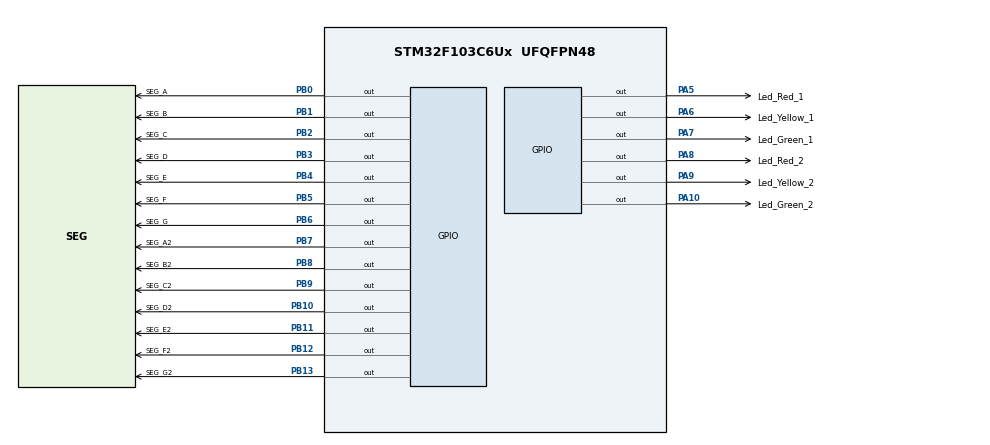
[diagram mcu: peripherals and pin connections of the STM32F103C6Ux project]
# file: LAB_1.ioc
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Mcu.Family=STM32F1
Mcu.Name=STM32F103C6Ux
Mcu.Package=UFQFPN48
NVIC.PriorityGroup=NVIC_PRIORITYGROUP_4
PA10.GPIO_Label=Led_Green_2
PA10.Signal=GPIO_Output
PA5.GPIO_Label=Led_Red_1
PA5.Signal=GPIO_Output
PA6.GPIO_Label=Led_Yellow_1
PA6.Signal=GPIO_Output
PA7.GPIO_Label=Led_Green_1
PA7.Signal=GPIO_Output
PA8.GPIO_Label=Led_Red_2
PA8.Signal=GPIO_Output
PA9.GPIO_Label=Led_Yellow_2
PA9.Signal=GPIO_Output
PB0.GPIO_Label=SEG_A
PB0.Signal=GPIO_Output
PB1.GPIO_Label=SEG_B
PB1.Signal=GPIO_Output
PB10.GPIO_Label=SEG_D2
PB10.Signal=GPIO_Output
PB11.GPIO_Label=SEG_E2
PB11.Signal=GPIO_Output
PB12.GPIO_Label=SEG_F2
PB12.Signal=GPIO_Output
PB13.GPIO_Label=SEG_G2
PB13.Signal=GPIO_Output
PB2.GPIO_Label=SEG_C
PB2.Signal=GPIO_Output
PB3.GPIO_Label=SEG_D
PB3.Signal=GPIO_Output
PB4.GPIO_Label=SEG_E
PB4.Signal=GPIO_Output
PB5.GPIO_Label=SEG_F
PB5.Signal=GPIO_Output
PB6.GPIO_Label=SEG_G
PB6.Signal=GPIO_Output
PB7.GPIO_Label=SEG_A2
PB7.Signal=GPIO_Output
PB8.GPIO_Label=SEG_B2
PB8.Signal=GPIO_Output
PB9.GPIO_Label=SEG_C2
PB9.Signal=GPIO_Output
ProjectManager.HeapSize=0x200
ProjectManager.StackSize=0x400
ProjectManager.TargetToolchain=STM32CubeIDE
RCC.APB1Freq_Value=8000000
RCC.APB2Freq_Value=8000000
VP_SYS_VS_ND.Mode=No_Debug
board=custom

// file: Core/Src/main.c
/* USER CODE BEGIN Header */
/**
  ******************************************************************************
  * @file           : main.c
  * @brief          : Main program body
  ******************************************************************************
  * @attention
  *
  * <h2><center>&copy; Copyright (c) 2024 STMicroelectronics.
  * All rights reserved.</center></h2>
  *
  * This software component is licensed by ST under BSD 3-Clause license,
  * the "License"; You may not use this file except in compliance with the
  * License. You may obtain a copy of the License at:
  *                        opensource.org/licenses/BSD-3-Clause
  *
  ******************************************************************************
  */
/* USER CODE END Header */
#include "main.h"

void SystemClock_Config(void);
static void MX_GPIO_Init(void);

int main(void)
{

  /* MCU Configuration--------------------------------------------------------*/

  /* Reset of all peripherals, Initializes the Flash interface and the Systick. */
  HAL_Init();

  /* Configure the system clock */
  SystemClock_Config();

  /* Initialize all configured peripherals */
  MX_GPIO_Init();

  /* Infinite loop */
  /* USER CODE BEGIN WHILE */
  void setNumberOnClock(int num)
  {
  	switch(num)
  	{
  		case 0:
  			HAL_GPIO_WritePin(Led_12_GPIO_Port, Led_12_Pin, SET);
  			break;
  		case 1:
  			HAL_GPIO_WritePin(Led_1_GPIO_Port, Led_1_Pin, SET);
  			break;
  		case 2:
  			HAL_GPIO_WritePin(Led_2_GPIO_Port, Led_2_Pin, SET);
  			break;
  		case 3:
  			HAL_GPIO_WritePin(Led_3_GPIO_Port, Led_3_Pin, SET);
  			break;
  		case 4:
  			HAL_GPIO_WritePin(Led_4_GPIO_Port, Led_4_Pin, SET);
  			break;
  		case 5:
  			HAL_GPIO_WritePin(Led_5_GPIO_Port, Led_5_Pin, SET);
  			break;
  		case 6:
  			HAL_GPIO_WritePin(Led_6_GPIO_Port, Led_6_Pin, SET);
  			break;
  		case 7:
  			HAL_GPIO_WritePin(Led_7_GPIO_Port, Led_7_Pin, SET);
  			break;
  		case 8:
  			HAL_GPIO_WritePin(Led_8_GPIO_Port, Led_8_Pin, SET);
  			break;
  		case 9:
  			HAL_GPIO_WritePin(Led_9_GPIO_Port, Led_9_Pin, SET);
  			break;
  		case 10:
  			HAL_GPIO_WritePin(Led_10_GPIO_Port, Led_10_Pin, SET);
  			break;
  		case 11:
  			HAL_GPIO_WritePin(Led_11_GPIO_Port, Led_11_Pin, SET);
  			break;
  	}
  }

  void clearNumberOnClock(int num)
  {
  	switch(num)
  	{
  		case 0:
  			HAL_GPIO_WritePin(Led_12_GPIO_Port, Led_12_Pin, RESET);
  			break;
  		case 1:
  			HAL_GPIO_WritePin(Led_1_GPIO_Port, Led_1_Pin, RESET);
  			break;
  		case 2:
  			HAL_GPIO_WritePin(Led_2_GPIO_Port, Led_2_Pin, RESET);
  			break;
  		case 3:
  			HAL_GPIO_WritePin(Led_3_GPIO_Port, Led_3_Pin, RESET);
  			break;
  		case 4:
  			HAL_GPIO_WritePin(Led_4_GPIO_Port, Led_4_Pin, RESET);
  			break;
  		case 5:
  			HAL_GPIO_WritePin(Led_5_GPIO_Port, Led_5_Pin, RESET);
  			break;
  		case 6:
  			HAL_GPIO_WritePin(Led_6_GPIO_Port, Led_6_Pin, RESET);
  			break;
  		case 7:
  			HAL_GPIO_WritePin(Led_7_GPIO_Port, Led_7_Pin, RESET);
  			break;
  		case 8:
  			HAL_GPIO_WritePin(Led_8_GPIO_Port, Led_8_Pin, RESET);
  			break;
  		case 9:
  			HAL_GPIO_WritePin(Led_9_GPIO_Port, Led_9_Pin, RESET);
  			break;
  		case 10:
  			HAL_GPIO_WritePin(Led_10_GPIO_Port, Led_10_Pin, RESET);
  			break;
  		case 11:
  			HAL_GPIO_WritePin(Led_11_GPIO_Port, Led_11_Pin, RESET);
  			break;
  	}
  }
  int second = 0;
  int minutes = 0;
  int hour = 0;

  int counter_sec = 2;
  while (1)
  {
	  if (second >= 60)
	  {
		  second = 0;
		  minutes++;
		  if (minutes >= 60)
		  {
			  minutes = 0;
			  clearNumberOnClock(hour);
			  hour++;
			  if (hour >= 12)
			  {
				  hour = 0;
			  }
		  }
	  }
	  if (counter_sec <= 0)
	  {
		  second++;
		  counter_sec = 2;
	  }

	  if (second % 5 == 0)
	  {
		  if (second / 5 == 0) clearNumberOnClock(11);
		  else clearNumberOnClock(second / 5 - 1);
		  setNumberOnClock(second / 5);
	  }

	  setNumberOnClock(hour);
	    setNumberOnClock(minutes / 5);
	  counter_sec--;

	  HAL_Delay(500);

  }
  /* USER CODE END 3 */
}

void SystemClock_Config(void)
{
  RCC_OscInitTypeDef RCC_OscInitStruct = {0};
  RCC_ClkInitTypeDef RCC_ClkInitStruct = {0};

  /** Initializes the RCC Oscillators according to the specified parameters
  * in the RCC_OscInitTypeDef structure.
  */
  RCC_OscInitStruct.OscillatorType = RCC_OSCILLATORTYPE_HSI;
  RCC_OscInitStruct.HSIState = RCC_HSI_ON;
  RCC_OscInitStruct.HSICalibrationValue = RCC_HSICALIBRATION_DEFAULT;
  RCC_OscInitStruct.PLL.PLLState = RCC_PLL_NONE;
  if (HAL_RCC_OscConfig(&RCC_OscInitStruct) != HAL_OK)
  {
    Error_Handler();
  }
  /** Initializes the CPU, AHB and APB buses clocks
  */
  RCC_ClkInitStruct.ClockType = RCC_CLOCKTYPE_HCLK|RCC_CLOCKTYPE_SYSCLK
                              |RCC_CLOCKTYPE_PCLK1|RCC_CLOCKTYPE_PCLK2;
  RCC_ClkInitStruct.SYSCLKSource = RCC_SYSCLKSOURCE_HSI;
  RCC_ClkInitStruct.AHBCLKDivider = RCC_SYSCLK_DIV1;
  RCC_ClkInitStruct.APB1CLKDivider = RCC_HCLK_DIV1;
  RCC_ClkInitStruct.APB2CLKDivider = RCC_HCLK_DIV1;

  if (HAL_RCC_ClockConfig(&RCC_ClkInitStruct, FLASH_LATENCY_0) != HAL_OK)
  {
    Error_Handler();
  }
}

static void MX_GPIO_Init(void)
{
  GPIO_InitTypeDef GPIO_InitStruct = {0};

  /* GPIO Ports Clock Enable */
  __HAL_RCC_GPIOA_CLK_ENABLE();

  /*Configure GPIO pin Output Level */
  HAL_GPIO_WritePin(GPIOA, Led_1_Pin|Led_2_Pin|Led_3_Pin|Led_4_Pin
                          |Led_5_Pin|Led_6_Pin|Led_7_Pin|Led_8_Pin
                          |Led_9_Pin|Led_10_Pin|Led_11_Pin|Led_12_Pin, GPIO_PIN_RESET);

  /*Configure GPIO pins : Led_1_Pin Led_2_Pin Led_3_Pin Led_4_Pin
                           Led_5_Pin Led_6_Pin Led_7_Pin Led_8_Pin
                           Led_9_Pin Led_10_Pin Led_11_Pin Led_12_Pin */
  GPIO_InitStruct.Pin = Led_1_Pin|Led_2_Pin|Led_3_Pin|Led_4_Pin
                          |Led_5_Pin|Led_6_Pin|Led_7_Pin|Led_8_Pin
                          |Led_9_Pin|Led_10_Pin|Led_11_Pin|Led_12_Pin;
  GPIO_InitStruct.Mode = GPIO_MODE_OUTPUT_PP;
  GPIO_InitStruct.Pull = GPIO_NOPULL;
  GPIO_InitStruct.Speed = GPIO_SPEED_FREQ_LOW;
  HAL_GPIO_Init(GPIOA, &GPIO_InitStruct);

}

void Error_Handler(void)
{
  __disable_irq();
  while (1)
  {
  }
}

/************************ (C) COPYRIGHT STMicroelectronics *****END OF FILE****/
